VERSION 5.8 ;
BUSBITCHARS "[]" ;
DIVIDERCHAR "/" ;

UNITS
  DATABASE MICRONS 1000 ;
END UNITS

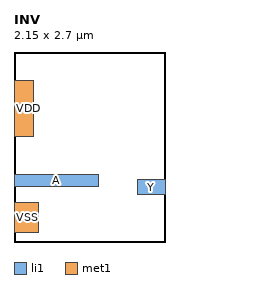
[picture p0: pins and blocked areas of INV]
MACRO INV
  CLASS CORE ;
  FOREIGN INV 0.000 0.000 ;
  ORIGIN 0.000 0.000 ;
  SIZE 2.150 BY 2.700 ;
  SITE unithd ;
  PIN A
    DIRECTION INPUT ;
    USE SIGNAL ;
    PORT
      LAYER li1 ;
        RECT 0.000 0.790 1.200 0.960 ;
    END
  END A
  PIN Y
    DIRECTION OUTPUT ;
    USE SIGNAL ;
    PORT
      LAYER li1 ;
        RECT 1.750 0.670 2.150 0.890 ;
    END
  END Y
  PIN VDD
    DIRECTION INOUT ;
    USE POWER ;
    PORT
      LAYER met1 ;
        RECT 0.000 1.500 0.280 2.300 ;
    END
  END VDD
  PIN VSS
    DIRECTION INOUT ;
    USE GROUND ;
    PORT
      LAYER met1 ;
        RECT 0.000 0.140 0.350 0.560 ;
    END
  END VSS
END INV

END LIBRARY
